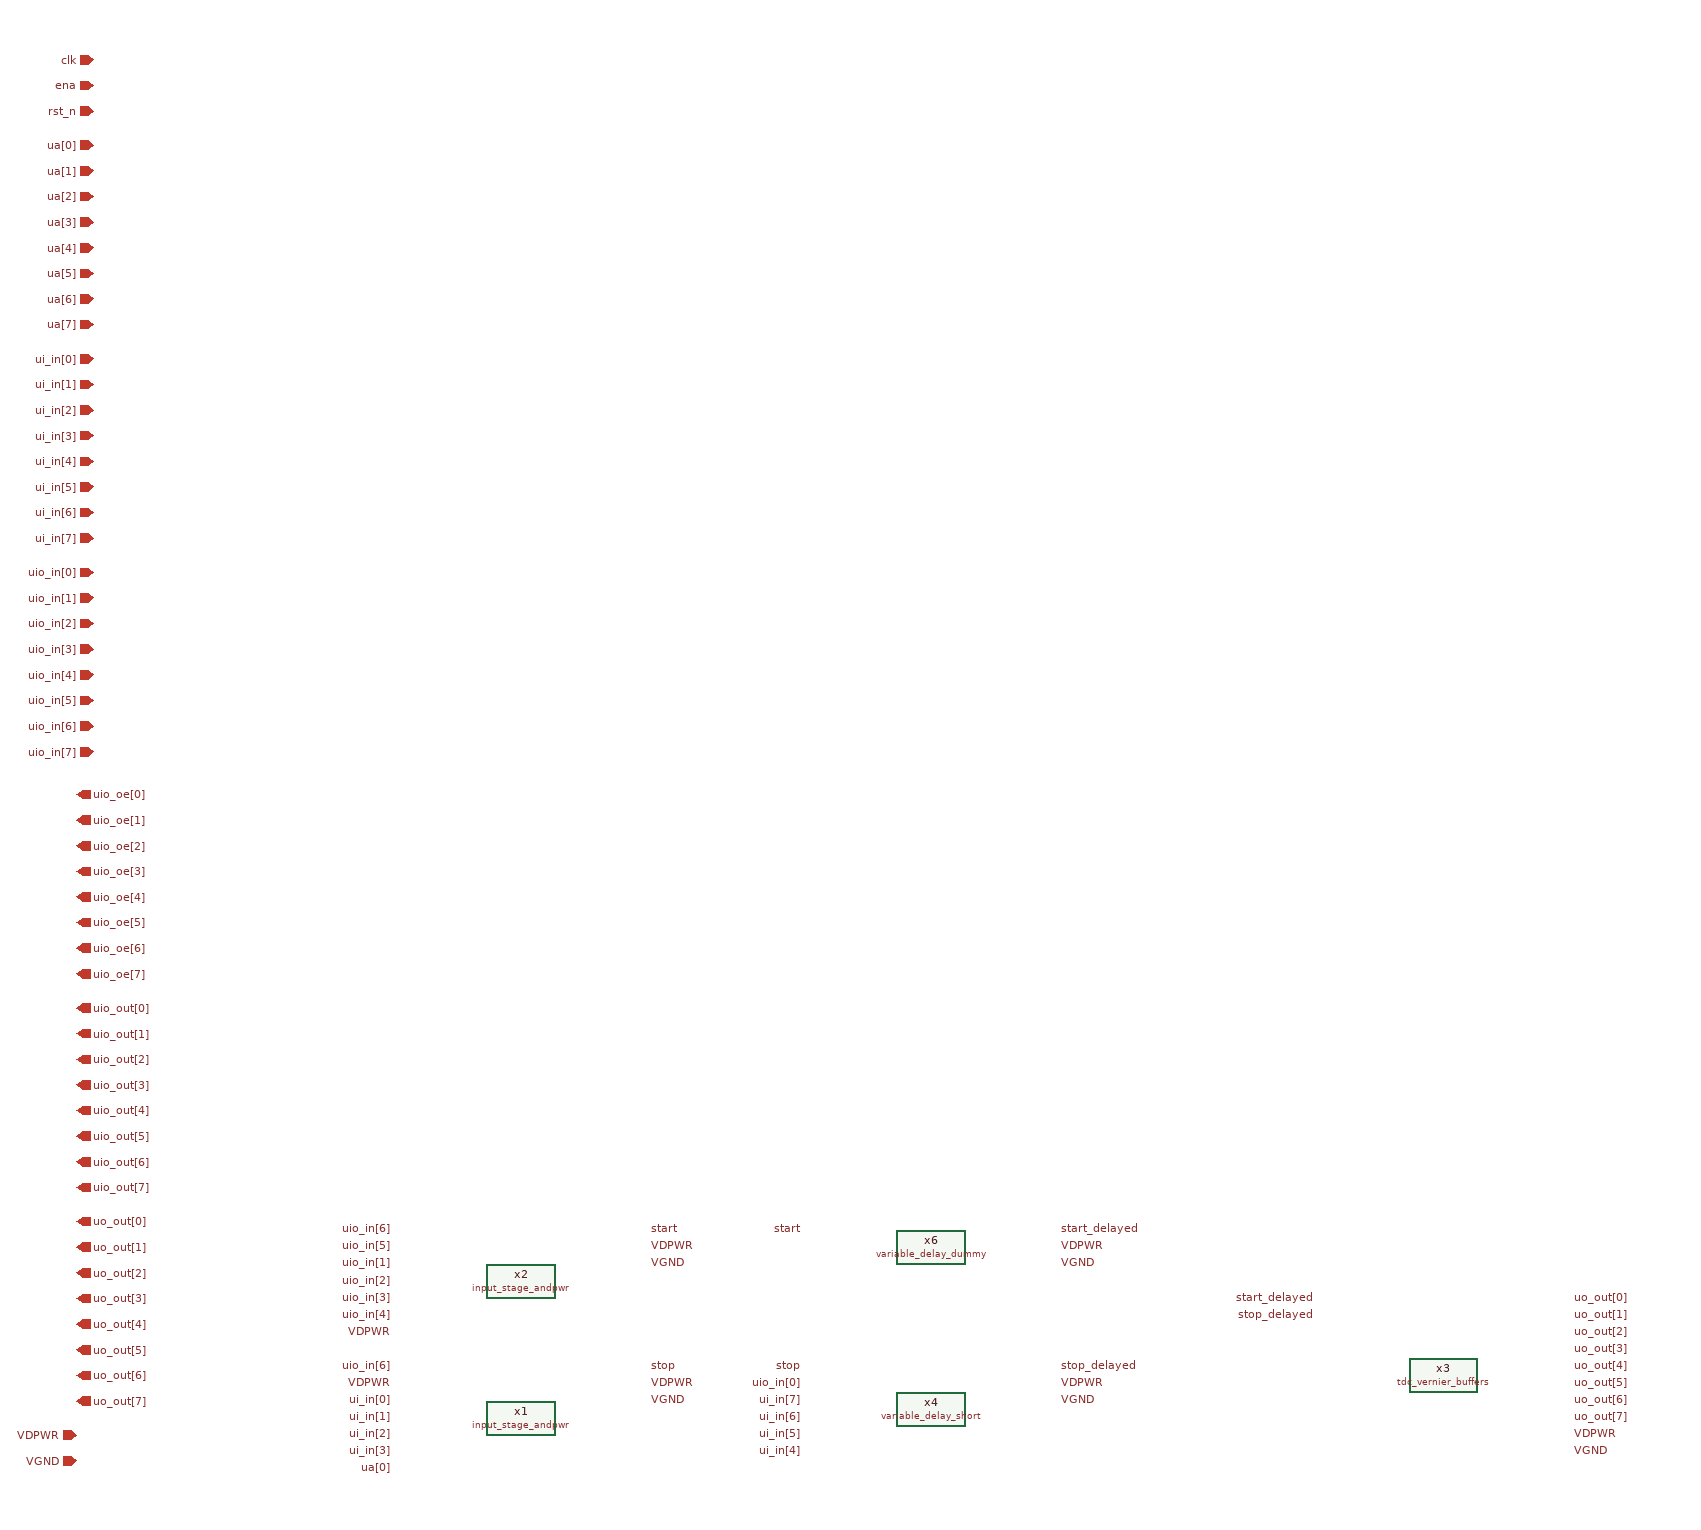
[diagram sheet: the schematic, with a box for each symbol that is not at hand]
v {xschem version=3.4.5 file_version=1.2
}
G {}
K {}
V {}
S {}
E {}
C {devices/lab_pin.sym} 750 -270 0 1 {name=p9 sig_type=std_logic lab=stop}
C {devices/lab_pin.sym} 1830 -190 0 1 {name=p21 sig_type=std_logic lab=VDPWR}
C {devices/lab_pin.sym} 1830 -330 0 1 {name=p22 sig_type=std_logic lab=uo_out[1]}
C {devices/lab_pin.sym} 1530 -350 0 0 {name=p27 sig_type=std_logic lab=start_delayed}
C {devices/lab_pin.sym} 1530 -330 0 0 {name=p28 sig_type=std_logic lab=stop_delayed}
C {devices/lab_pin.sym} 750 -430 0 1 {name=p42 sig_type=std_logic lab=start}
C {devices/lab_pin.sym} 450 -410 0 0 {name=p45x sig_type=std_logic lab=uio_in[5]}
C {devices/lab_pin.sym} 1230 -270 0 1 {name=p48 sig_type=std_logic lab=stop_delayed}
C {devices/lab_pin.sym} 930 -270 0 0 {name=p49 sig_type=std_logic lab=stop}
C {devices/lab_pin.sym} 930 -430 0 0 {name=p18 sig_type=std_logic lab=start}
C {devices/lab_pin.sym} 1230 -430 0 1 {name=p20 sig_type=std_logic lab=start_delayed}
C {devices/iopin.sym} 80 -190 0 0 {name=p1x lab=VDPWR}
C {devices/ipin.sym} 100 -1700 0 0 {name=p4 lab=ua[0]}
C {devices/opin.sym} 80 -440 0 0 {name=p6x lab=uo_out[0]}
C {devices/iopin.sym} 80 -160 0 0 {name=p2x lab=VGND}
C {devices/ipin.sym} 100 -1450 0 0 {name=p17 lab=ui_in[0]}
C {devices/opin.sym} 80 -410 0 0 {name=p10x lab=uo_out[1]}
C {devices/opin.sym} 80 -380 0 0 {name=p13x lab=uo_out[2]}
C {devices/opin.sym} 80 -350 0 0 {name=p14x lab=uo_out[3]}
C {devices/opin.sym} 80 -320 0 0 {name=p15x lab=uo_out[4]}
C {devices/opin.sym} 80 -290 0 0 {name=p17x lab=uo_out[5]}
C {devices/opin.sym} 80 -260 0 0 {name=p19x lab=uo_out[6]}
C {devices/opin.sym} 80 -230 0 0 {name=p29x lab=uo_out[7]}
C {devices/lab_pin.sym} 1830 -350 0 1 {name=p23 sig_type=std_logic lab=uo_out[0]}
C {devices/lab_pin.sym} 1830 -310 0 1 {name=p24 sig_type=std_logic lab=uo_out[2]}
C {devices/lab_pin.sym} 1830 -290 0 1 {name=p25 sig_type=std_logic lab=uo_out[3]}
C {devices/lab_pin.sym} 1830 -270 0 1 {name=p26 sig_type=std_logic lab=uo_out[4]}
C {devices/lab_pin.sym} 1830 -250 0 1 {name=p30 sig_type=std_logic lab=uo_out[5]}
C {devices/lab_pin.sym} 1830 -230 0 1 {name=p31 sig_type=std_logic lab=uo_out[6]}
C {devices/lab_pin.sym} 1830 -210 0 1 {name=p32 sig_type=std_logic lab=uo_out[7]}
C {devices/lab_pin.sym} 1830 -170 0 1 {name=p33 sig_type=std_logic lab=VGND}
C {devices/lab_pin.sym} 1230 -230 0 1 {name=p34 sig_type=std_logic lab=VGND}
C {devices/lab_pin.sym} 1230 -390 0 1 {name=p35 sig_type=std_logic lab=VGND}
C {devices/lab_pin.sym} 750 -390 0 1 {name=p36 sig_type=std_logic lab=VGND}
C {devices/lab_pin.sym} 750 -230 0 1 {name=p37 sig_type=std_logic lab=VGND}
C {devices/lab_pin.sym} 1230 -250 0 1 {name=p39 sig_type=std_logic lab=VDPWR}
C {devices/lab_pin.sym} 1230 -410 0 1 {name=p43 sig_type=std_logic lab=VDPWR}
C {devices/lab_pin.sym} 750 -410 0 1 {name=p44 sig_type=std_logic lab=VDPWR}
C {devices/lab_pin.sym} 750 -250 0 1 {name=p47 sig_type=std_logic lab=VDPWR}
C {devices/ipin.sym} 100 -1420 0 0 {name=p7x lab=ui_in[1]}
C {devices/ipin.sym} 100 -1390 0 0 {name=p8x lab=ui_in[2]}
C {devices/ipin.sym} 100 -1360 0 0 {name=p38x lab=ui_in[3]}
C {devices/ipin.sym} 100 -1330 0 0 {name=p41x lab=ui_in[4]}
C {devices/ipin.sym} 100 -1300 0 0 {name=p46x lab=ui_in[5]}
C {devices/ipin.sym} 100 -1270 0 0 {name=p54x lab=ui_in[6]}
C {devices/ipin.sym} 100 -1240 0 0 {name=p55x lab=ui_in[7]}
C {devices/ipin.sym} 100 -1200 0 0 {name=p56x lab=uio_in[0]}
C {devices/ipin.sym} 100 -1170 0 0 {name=p57x lab=uio_in[1]}
C {devices/ipin.sym} 100 -1140 0 0 {name=p58x lab=uio_in[2]}
C {devices/ipin.sym} 100 -1110 0 0 {name=p59x lab=uio_in[3]}
C {devices/ipin.sym} 100 -1080 0 0 {name=p60x lab=uio_in[4]}
C {devices/ipin.sym} 100 -1050 0 0 {name=p61x lab=uio_in[5]}
C {devices/lab_pin.sym} 450 -390 0 0 {name=p5x sig_type=std_logic lab=uio_in[1]}
C {devices/lab_pin.sym} 450 -370 0 0 {name=p40x sig_type=std_logic lab=uio_in[2]}
C {devices/lab_pin.sym} 450 -350 0 0 {name=p53x sig_type=std_logic lab=uio_in[3]}
C {devices/lab_pin.sym} 450 -330 0 0 {name=p62x sig_type=std_logic lab=uio_in[4]}
C {devices/lab_pin.sym} 450 -230 0 0 {name=p63 sig_type=std_logic lab=ui_in[0]}
C {devices/lab_pin.sym} 450 -210 0 0 {name=p64 sig_type=std_logic lab=ui_in[1]}
C {devices/lab_pin.sym} 450 -190 0 0 {name=p65 sig_type=std_logic lab=ui_in[2]}
C {devices/lab_pin.sym} 450 -170 0 0 {name=p66 sig_type=std_logic lab=ui_in[3]}
C {devices/lab_pin.sym} 450 -250 2 1 {name=p67 sig_type=std_logic lab=VDPWR}
C {devices/lab_pin.sym} 930 -170 0 0 {name=p11 sig_type=std_logic lab=ui_in[4]}
C {devices/lab_pin.sym} 930 -190 0 0 {name=p50 sig_type=std_logic lab=ui_in[5]}
C {devices/lab_pin.sym} 930 -210 0 0 {name=p51 sig_type=std_logic lab=ui_in[6]}
C {devices/lab_pin.sym} 930 -230 0 0 {name=p52 sig_type=std_logic lab=ui_in[7]}
C {devices/lab_pin.sym} 930 -250 0 0 {name=p68 sig_type=std_logic lab=uio_in[0]}
C {variable_delay_short.sym} 1080 -220 0 0 {name=x4}
C {variable_delay_dummy.sym} 1080 -410 0 0 {name=x6}
C {devices/lab_pin.sym} 450 -150 0 0 {name=p12 sig_type=std_logic lab=ua[0]}
C {devices/ipin.sym} 100 -1020 0 0 {name=p69x lab=uio_in[6]}
C {devices/ipin.sym} 100 -990 0 0 {name=p70x lab=uio_in[7]}
C {devices/opin.sym} 80 -690 0 0 {name=p71x lab=uio_out[0]}
C {devices/opin.sym} 80 -660 0 0 {name=p72x lab=uio_out[1]}
C {devices/opin.sym} 80 -630 0 0 {name=p73x lab=uio_out[2]}
C {devices/opin.sym} 80 -600 0 0 {name=p74x lab=uio_out[3]}
C {devices/opin.sym} 80 -570 0 0 {name=p75x lab=uio_out[4]}
C {devices/opin.sym} 80 -540 0 0 {name=p76x lab=uio_out[5]}
C {devices/opin.sym} 80 -510 0 0 {name=p77x lab=uio_out[6]}
C {devices/opin.sym} 80 -480 0 0 {name=p78x lab=uio_out[7]}
C {devices/opin.sym} 80 -940 0 0 {name=p79x lab=uio_oe[0]}
C {devices/opin.sym} 80 -910 0 0 {name=p80x lab=uio_oe[1]}
C {devices/opin.sym} 80 -880 0 0 {name=p81x lab=uio_oe[2]}
C {devices/opin.sym} 80 -850 0 0 {name=p82x lab=uio_oe[3]}
C {devices/opin.sym} 80 -820 0 0 {name=p83x lab=uio_oe[4]}
C {devices/opin.sym} 80 -790 0 0 {name=p84x lab=uio_oe[5]}
C {devices/opin.sym} 80 -760 0 0 {name=p85x lab=uio_oe[6]}
C {devices/opin.sym} 80 -730 0 0 {name=p86x lab=uio_oe[7]}
C {devices/ipin.sym} 100 -1670 0 0 {name=p6 lab=ua[1]}
C {devices/ipin.sym} 100 -1640 0 0 {name=p7 lab=ua[2]}
C {devices/ipin.sym} 100 -1610 0 0 {name=p8 lab=ua[3]}
C {devices/ipin.sym} 100 -1580 0 0 {name=p10 lab=ua[4]}
C {devices/ipin.sym} 100 -1550 0 0 {name=p13 lab=ua[5]}
C {devices/ipin.sym} 100 -1520 0 0 {name=p14 lab=ua[6]}
C {devices/ipin.sym} 100 -1490 0 0 {name=p15 lab=ua[7]}
C {devices/ipin.sym} 100 -1770 0 0 {name=p2 lab=ena}
C {devices/ipin.sym} 100 -1800 0 0 {name=p1 lab=clk sim_pinnumber=1}
C {devices/ipin.sym} 100 -1740 0 0 {name=p3 lab=rst_n}
C {tdc_vernier_buffers.sym} 1680 -260 0 0 {name=x3}
C {devices/noconn.sym} 80 -690 0 0 {name=l1}
C {devices/noconn.sym} 80 -660 0 0 {name=l2}
C {devices/noconn.sym} 80 -630 0 0 {name=l3}
C {devices/noconn.sym} 80 -600 0 0 {name=l4}
C {devices/noconn.sym} 80 -570 0 0 {name=l5}
C {devices/noconn.sym} 80 -540 0 0 {name=l6}
C {devices/noconn.sym} 80 -510 0 0 {name=l7}
C {devices/noconn.sym} 80 -480 0 0 {name=l8}
C {devices/noconn.sym} 80 -940 0 0 {name=l9}
C {devices/noconn.sym} 80 -910 0 0 {name=l10}
C {devices/noconn.sym} 80 -880 0 0 {name=l11}
C {devices/noconn.sym} 80 -850 0 0 {name=l12}
C {devices/noconn.sym} 80 -820 0 0 {name=l13}
C {devices/noconn.sym} 80 -790 0 0 {name=l14}
C {devices/noconn.sym} 80 -760 0 0 {name=l15}
C {devices/noconn.sym} 80 -730 0 0 {name=l16}
C {devices/noconn.sym} 100 -990 2 0 {name=l17}
C {devices/noconn.sym} 100 -1490 2 0 {name=l19}
C {devices/noconn.sym} 100 -1520 2 0 {name=l20}
C {devices/noconn.sym} 100 -1550 2 0 {name=l21}
C {devices/noconn.sym} 100 -1580 2 0 {name=l22}
C {devices/noconn.sym} 100 -1610 2 0 {name=l23}
C {devices/noconn.sym} 100 -1640 2 0 {name=l24}
C {devices/noconn.sym} 100 -1670 2 0 {name=l25}
C {devices/noconn.sym} 100 -1740 2 0 {name=l26}
C {devices/noconn.sym} 100 -1800 2 0 {name=l27}
C {devices/noconn.sym} 100 -1770 2 0 {name=l28}
C {input_stage_andpwr.sym} 600 -210 0 0 {name=x1}
C {input_stage_andpwr.sym} 600 -370 0 0 {name=x2}
C {devices/lab_pin.sym} 450 -430 0 0 {name=p5 sig_type=std_logic lab=uio_in[6]}
C {devices/lab_pin.sym} 450 -270 0 0 {name=p16 sig_type=std_logic lab=uio_in[6]}
C {devices/lab_pin.sym} 450 -310 2 1 {name=p19 sig_type=std_logic lab=VDPWR}
